One B-rep face of a CAD part: STEP entity #158.
In plain terms, the planar face has unit normal (0, 0, -1).
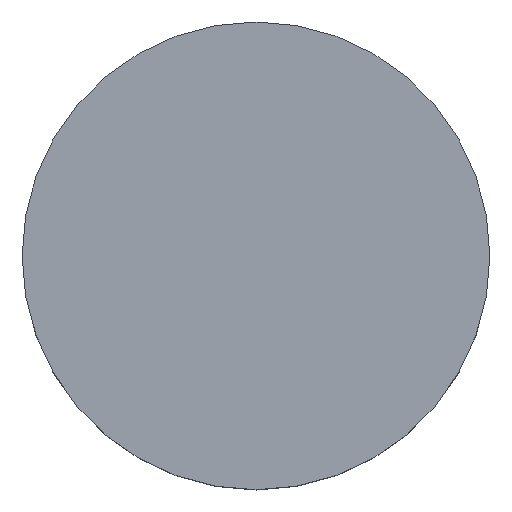
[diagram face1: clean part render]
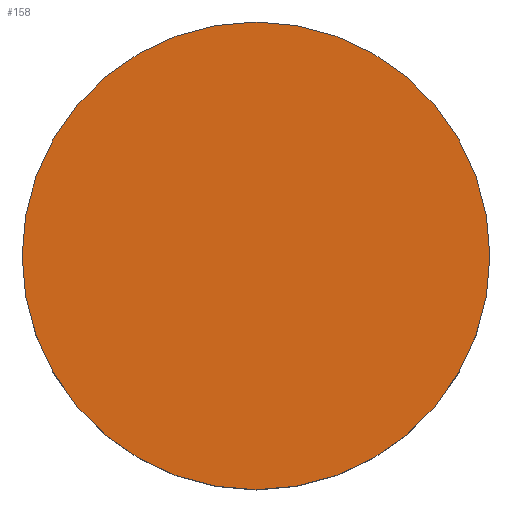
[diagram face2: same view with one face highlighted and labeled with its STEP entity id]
Its self-contained STEP definition (entity closure, numbers rounded to 3 decimals):
#49 = CYLINDRICAL_SURFACE('',#50,2.85);
#50 = AXIS2_PLACEMENT_3D('',#51,#52,#53);
#51 = CARTESIAN_POINT('',(0.,0.,-1.65));
#52 = DIRECTION('',(0.,0.,1.));
#53 = DIRECTION('',(1.,0.,-0.));
#74 = VERTEX_POINT('',#75);
#75 = CARTESIAN_POINT('',(2.85,0.,-1.65));
#96 = EDGE_CURVE('',#74,#74,#97,.T.);
#97 = SURFACE_CURVE('',#98,(#103,#110),.PCURVE_S1.);
#98 = CIRCLE('',#99,2.85);
#99 = AXIS2_PLACEMENT_3D('',#100,#101,#102);
#100 = CARTESIAN_POINT('',(0.,0.,-1.65));
#101 = DIRECTION('',(0.,0.,1.));
#102 = DIRECTION('',(1.,0.,-0.));
#103 = PCURVE('',#49,#104);
#104 = DEFINITIONAL_REPRESENTATION('',(#105),#109);
#105 = LINE('',#106,#107);
#106 = CARTESIAN_POINT('',(0.,0.));
#107 = VECTOR('',#108,1.);
#108 = DIRECTION('',(1.,0.));
#109 = ( GEOMETRIC_REPRESENTATION_CONTEXT(2) 
PARAMETRIC_REPRESENTATION_CONTEXT() REPRESENTATION_CONTEXT('2D SPACE',''
  ) );
#110 = PCURVE('',#111,#116);
#111 = PLANE('',#112);
#112 = AXIS2_PLACEMENT_3D('',#113,#114,#115);
#113 = CARTESIAN_POINT('',(0.,0.,-1.65));
#114 = DIRECTION('',(0.,0.,1.));
#115 = DIRECTION('',(1.,0.,-0.));
#116 = DEFINITIONAL_REPRESENTATION('',(#117),#121);
#117 = CIRCLE('',#118,2.85);
#118 = AXIS2_PLACEMENT_2D('',#119,#120);
#119 = CARTESIAN_POINT('',(0.,0.));
#120 = DIRECTION('',(1.,0.));
#121 = ( GEOMETRIC_REPRESENTATION_CONTEXT(2) 
PARAMETRIC_REPRESENTATION_CONTEXT() REPRESENTATION_CONTEXT('2D SPACE',''
  ) );
#158 = ADVANCED_FACE('',(#159),#111,.F.);
#159 = FACE_BOUND('',#160,.T.);
#160 = EDGE_LOOP('',(#161));
#161 = ORIENTED_EDGE('',*,*,#96,.F.);
